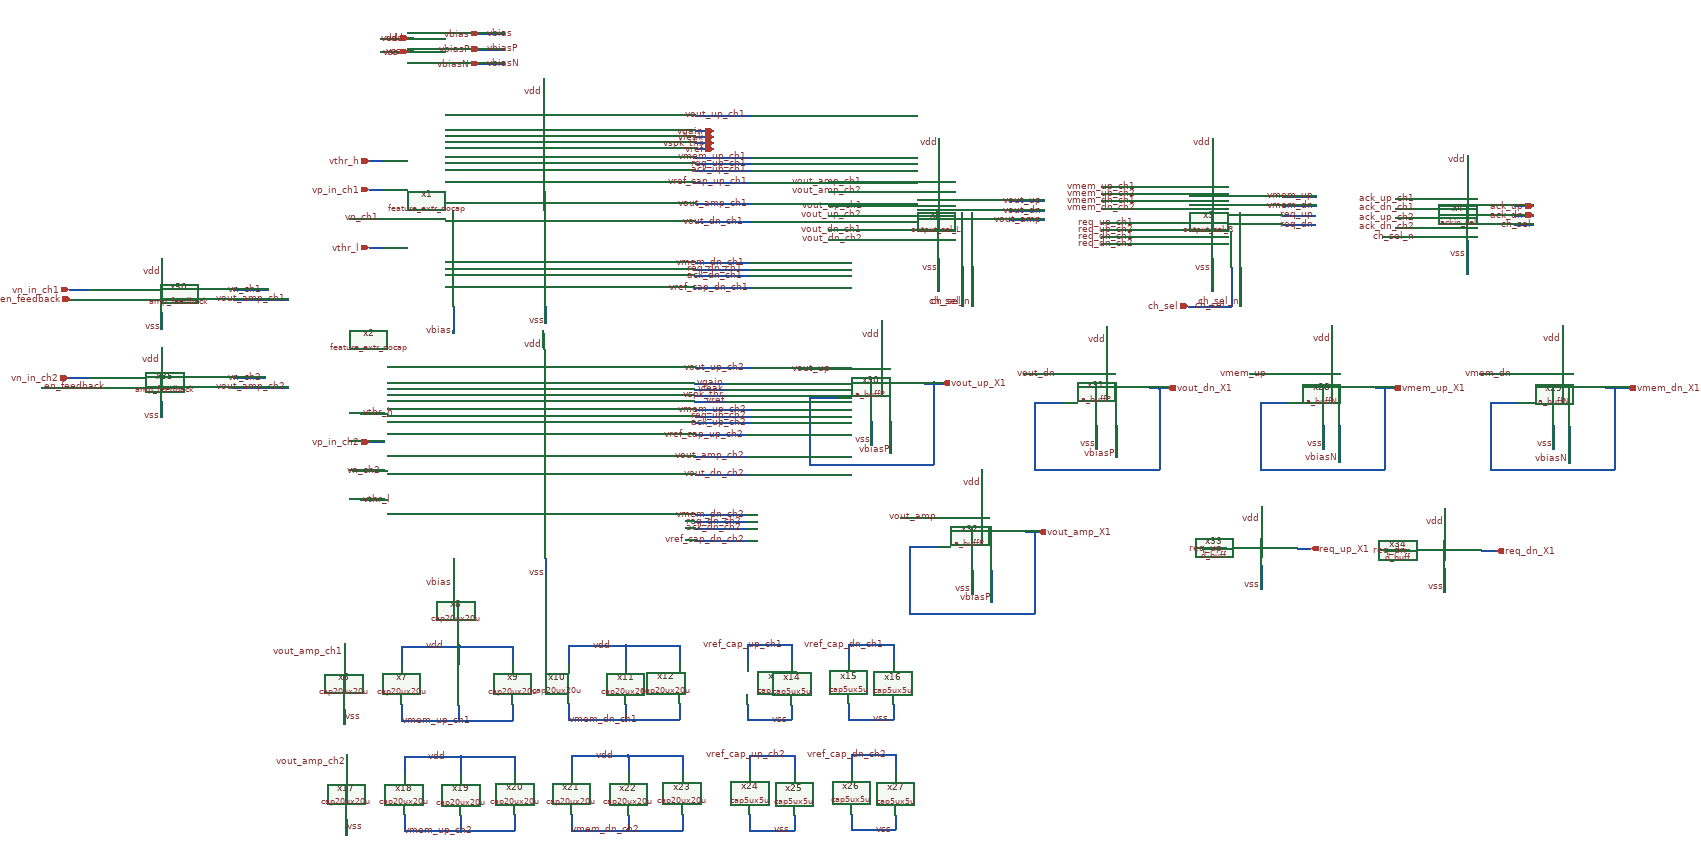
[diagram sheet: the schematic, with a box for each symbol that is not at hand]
v {xschem version=3.4.8RC file_version=1.3}
G {}
K {}
V {}
S {}
F {}
E {}
N 186.25 -1198.75 253.75 -1198.75 {lab=vdd}
N 186.25 -1171.25 253.75 -1171.25 {lab=vss}
N 388.75 -1208.75 443.75 -1208.75 {lab=vbias}
N 525 -1115 525 -1080 {lab=vdd}
N 530 -638.75 530 -603.75 {lab=vss}
N 525 -583.75 525 -555 {lab=vdd}
N 337.5 -640 337.5 -582.5 {lab=vbias}
N 530 -113.75 530 -78.75 {lab=vss}
N 337.5 -115 337.5 -57.5 {lab=vbias}
N 162.5 -943.75 193.75 -943.75 {lab=vthr_h}
N 162.5 -762.5 193.75 -762.5 {lab=vthr_l}
N 162.5 -883.75 193.75 -883.75 {lab=vp_in_ch1}
N 143.75 -417.5 193.75 -417.5 {lab=vthr_h}
N 143.75 -236.25 193.75 -236.25 {lab=vthr_l}
N 842.5 -1006.25 880 -1006.25 {lab=vgain}
N 842.5 -993.75 880 -993.75 {lab=vleak}
N 842.5 -981.25 880 -981.25 {lab=vspk_thr}
N 842.5 -968.75 880 -968.75 {lab=vref}
N 842.5 -937.5 962.5 -937.5 {lab=req_up_ch1}
N 842.5 -1038.75 961.25 -1038.75 {lab=vout_up_ch1}
N 842.5 -816.25 961.25 -816.25 {lab=vout_dn_ch1}
N 842.5 -411.25 960 -411.25 {lab=req_up_ch2}
N 842.5 -512.5 960 -512.5 {lab=vout_up_ch2}
N 843.75 -397.5 960 -397.5 {lab=ack_up_ch2}
N 843.75 -177.5 952.5 -177.5 {lab=ack_dn_ch2}
N 842.5 -923.75 962.5 -923.75 {lab=ack_up_ch1}
N 841.25 -703.75 957.5 -703.75 {lab=ack_dn_ch1}
N 841.25 -717.5 956.25 -717.5 {lab=req_dn_ch1}
N 842.5 -290 953.75 -290 {lab=vout_dn_ch2}
N 842.5 -372.5 946.25 -372.5 {lab=vref_cap_up_ch2}
N 842.5 -898.75 957.5 -898.75 {lab=vref_cap_up_ch1}
N 841.25 -191.25 951.25 -191.25 {lab=req_dn_ch2}
N 838.75 -951.25 962.5 -951.25 {lab=vmem_up_ch1}
N 842.5 -853.75 958.75 -853.75 {lab=vout_amp_ch1}
N 842.5 -731.25 956.25 -731.25 {lab=vmem_dn_ch1}
N 841.25 -678.75 958.75 -678.75 {lab=vref_cap_dn_ch1}
N 110 63.75 110 110 {lab=vout_amp_ch1}
N 110 200 110 232.5 {lab=vss}
N 230 190 230 223.75 {lab=vmem_up_ch1}
N 461.25 190 461.25 223.75 {lab=vmem_up_ch1}
N 348.75 192.5 348.75 223.75 {lab=vmem_up_ch1}
N 230 68.75 230 106.25 {lab=vdd}
N 461.25 68.75 461.25 105 {lab=vdd}
N 348.75 68.75 348.75 106.25 {lab=vdd}
N 842.5 -425 958.75 -425 {lab=vmem_up_ch2}
N 842.5 -327.5 951.25 -327.5 {lab=vout_amp_ch2}
N 842.5 -205 950 -205 {lab=vmem_dn_ch2}
N 841.25 -152.5 951.25 -152.5 {lab=vref_cap_dn_ch2}
N 841.25 -480 907.5 -480 {lab=vgain}
N 841.25 -467.5 907.5 -467.5 {lab=vleak}
N 841.25 -455 907.5 -455 {lab=vspk_thr}
N 841.25 -442.5 907.5 -442.5 {lab=vref}
N 162.5 -357.5 193.75 -357.5 {lab=vp_in_ch2}
N 1960 -720 1960 -640 {lab=ch_sel}
N 1870 -640 1960 -640 {lab=ch_sel}
N 1920 -740 1920 -670 {lab=vss}
N 1920 -990 1920 -930 {lab=vdd}
N 1120 -900 1200 -900 {lab=vout_amp_ch1}
N 1120 -880 1200 -880 {lab=vout_amp_ch2}
N 1120 -850 1200 -850 {lab=vout_up_ch1}
N 1120 -830 1200 -830 {lab=vout_up_ch2}
N 1120 -800 1200 -800 {lab=vout_dn_ch1}
N 1120 -780 1200 -780 {lab=vout_dn_ch2}
N 1690 -890 1770 -890 {lab=vmem_up_ch1}
N 1690 -875 1770 -875 {lab=vmem_up_ch2}
N 1690 -860 1770 -860 {lab=vmem_dn_ch1}
N 1690 -845 1770 -845 {lab=vmem_dn_ch2}
N 1690 -815 1770 -815 {lab=req_up_ch1}
N 1690 -800 1770 -800 {lab=req_up_ch2}
N 1690 -785 1770 -785 {lab=req_dn_ch1}
N 1690 -770 1770 -770 {lab=req_dn_ch2}
N 2067.5 -850 2137.5 -850 {lab=vmem_dn}
N 2067.5 -830 2135 -830 {lab=req_up}
N 2452.5 -955 2452.5 -895 {lab=vdd}
N 2452.5 -776.25 2452.5 -706.25 {lab=vss}
N 2550 -810 2591.25 -810 {lab=ch_sel}
N 2550 -830 2591.25 -830 {lab=ack_dn}
N 2550 -850 2591.25 -850 {lab=ack_up}
N 2302.5 -865 2352.5 -865 {lab=ack_up_ch1}
N 2302.5 -845 2352.5 -845 {lab=ack_dn_ch1}
N 2302.5 -825 2352.5 -825 {lab=ack_up_ch2}
N 2302.5 -805 2352.5 -805 {lab=ack_dn_ch2}
N 1980 -720 1980 -640 {lab=ch_sel_n}
N 2275 -785 2355 -785 {lab=ch_sel_n}
N 1420 -723.75 1420 -640 {lab=ch_sel_n}
N 1400 -723.75 1400 -640 {lab=ch_sel}
N 1350 -990 1350 -930 {lab=vdd}
N 1350 -740 1350 -670 {lab=vss}
N 230 68.75 348.75 68.75 {lab=vdd}
N 348.75 68.75 461.25 68.75 {lab=vdd}
N 230 223.75 348.75 223.75 {lab=vmem_up_ch1}
N 348.75 223.75 461.25 223.75 {lab=vmem_up_ch1}
N 578.75 188.75 578.75 222.5 {lab=vmem_dn_ch1}
N 810 188.75 810 222.5 {lab=vmem_dn_ch1}
N 697.5 191.25 697.5 222.5 {lab=vmem_dn_ch1}
N 578.75 67.5 578.75 105 {lab=vdd}
N 810 67.5 810 103.75 {lab=vdd}
N 697.5 67.5 697.5 105 {lab=vdd}
N 578.75 67.5 697.5 67.5 {lab=vdd}
N 697.5 67.5 810 67.5 {lab=vdd}
N 578.75 222.5 697.5 222.5 {lab=vmem_dn_ch1}
N 697.5 222.5 810 222.5 {lab=vmem_dn_ch1}
N 951.25 66.25 951.25 101.25 {lab=vref_cap_up_ch1}
N 1043.75 66.25 1043.75 103.75 {lab=vref_cap_up_ch1}
N 951.25 66.25 1043.75 66.25 {lab=vref_cap_up_ch1}
N 951.25 190 951.25 222.5 {lab=vss}
N 951.25 222.5 1043.75 222.5 {lab=vss}
N 1043.75 192.5 1043.75 222.5 {lab=vss}
N 1162.5 65 1162.5 100 {lab=vref_cap_dn_ch1}
N 1255 65 1255 102.5 {lab=vref_cap_dn_ch1}
N 1162.5 65 1255 65 {lab=vref_cap_dn_ch1}
N 1162.5 188.75 1162.5 221.25 {lab=vss}
N 1162.5 221.25 1255 221.25 {lab=vss}
N 1255 191.25 1255 221.25 {lab=vss}
N 115 293.75 115 340 {lab=vout_amp_ch2}
N 115 430 115 462.5 {lab=vss}
N 235 420 235 453.75 {lab=vmem_up_ch2}
N 466.25 420 466.25 453.75 {lab=vmem_up_ch2}
N 353.75 422.5 353.75 453.75 {lab=vmem_up_ch2}
N 235 298.75 235 336.25 {lab=vdd}
N 466.25 298.75 466.25 335 {lab=vdd}
N 353.75 298.75 353.75 336.25 {lab=vdd}
N 235 298.75 353.75 298.75 {lab=vdd}
N 353.75 298.75 466.25 298.75 {lab=vdd}
N 235 453.75 353.75 453.75 {lab=vmem_up_ch2}
N 353.75 453.75 466.25 453.75 {lab=vmem_up_ch2}
N 583.75 418.75 583.75 452.5 {lab=vmem_dn_ch2}
N 815 418.75 815 452.5 {lab=vmem_dn_ch2}
N 702.5 421.25 702.5 452.5 {lab=vmem_dn_ch2}
N 583.75 297.5 583.75 335 {lab=vdd}
N 815 297.5 815 333.75 {lab=vdd}
N 702.5 297.5 702.5 335 {lab=vdd}
N 583.75 297.5 702.5 297.5 {lab=vdd}
N 702.5 297.5 815 297.5 {lab=vdd}
N 583.75 452.5 702.5 452.5 {lab=vmem_dn_ch2}
N 702.5 452.5 815 452.5 {lab=vmem_dn_ch2}
N 956.25 296.25 956.25 331.25 {lab=vref_cap_up_ch2}
N 1048.75 296.25 1048.75 333.75 {lab=vref_cap_up_ch2}
N 956.25 296.25 1048.75 296.25 {lab=vref_cap_up_ch2}
N 956.25 420 956.25 452.5 {lab=vss}
N 956.25 452.5 1048.75 452.5 {lab=vss}
N 1048.75 422.5 1048.75 452.5 {lab=vss}
N 1167.5 295 1167.5 330 {lab=vref_cap_dn_ch2}
N 1260 295 1260 332.5 {lab=vref_cap_dn_ch2}
N 1167.5 295 1260 295 {lab=vref_cap_dn_ch2}
N 1167.5 418.75 1167.5 451.25 {lab=vss}
N 1167.5 451.25 1260 451.25 {lab=vss}
N 1260 421.25 1260 451.25 {lab=vss}
N 1290 -140 1350 -140 {lab=vout_amp_X1}
N 1290 -140 1290 0 {lab=vout_amp_X1}
N 1290 0 1550 0 {lab=vout_amp_X1}
N 1550 -170 1550 0 {lab=vout_amp_X1}
N 1530 -170 1550 -170 {lab=vout_amp_X1}
N 1080 -450 1140 -450 {lab=vout_up_X1}
N 1080 -450 1080 -310 {lab=vout_up_X1}
N 1080 -310 1340 -310 {lab=vout_up_X1}
N 1340 -480 1340 -310 {lab=vout_up_X1}
N 1320 -480 1340 -480 {lab=vout_up_X1}
N 1550 -440 1610 -440 {lab=vout_dn_X1}
N 1550 -440 1550 -300 {lab=vout_dn_X1}
N 1550 -300 1810 -300 {lab=vout_dn_X1}
N 1810 -470 1810 -300 {lab=vout_dn_X1}
N 1790 -470 1810 -470 {lab=vout_dn_X1}
N 2020 -440 2080 -440 {lab=vmem_up_X1}
N 2020 -440 2020 -300 {lab=vmem_up_X1}
N 2020 -300 2280 -300 {lab=vmem_up_X1}
N 2280 -470 2280 -300 {lab=vmem_up_X1}
N 2260 -470 2280 -470 {lab=vmem_up_X1}
N 2500 -440 2560 -440 {lab=vmem_dn_X1}
N 2500 -440 2500 -300 {lab=vmem_dn_X1}
N 2500 -300 2760 -300 {lab=vmem_dn_X1}
N 2760 -470 2760 -300 {lab=vmem_dn_X1}
N 2760 -470 2790 -470 {lab=vmem_dn_X1}
N 2740 -470 2760 -470 {lab=vmem_dn_X1}
N 1270 -200 1350 -200 {lab=vout_amp}
N 1057.5 -510 1140 -510 {lab=vout_up}
N 1527.5 -500 1610 -500 {lab=vout_dn}
N 1997.5 -500 2080 -500 {lab=vmem_up}
N 2477.5 -500 2560 -500 {lab=vmem_dn}
N 1420 -90 1420 -40 {lab=vss}
N 1440 -300 1440 -250 {lab=vdd}
N 1460 -90 1460 -22.5 {lab=vbiasP}
N 1700 -598.75 1700 -548.75 {lab=vdd}
N 1680 -391.25 1680 -341.25 {lab=vss}
N 1720 -391.25 1720 -323.75 {lab=vbiasP}
N 1210 -400 1210 -350 {lab=vss}
N 1250 -400 1250 -332.5 {lab=vbiasP}
N 1230 -610 1230 -560 {lab=vdd}
N 2170 -600 2170 -550 {lab=vdd}
N 2650 -600 2650 -550 {lab=vdd}
N 2152.5 -391.25 2152.5 -341.25 {lab=vss}
N 2632.5 -391.25 2632.5 -341.25 {lab=vss}
N 2185 -391.25 2185 -313.75 {lab=vbiasN}
N 2665 -390 2665 -312.5 {lab=vbiasN}
N 1340 -480 1360 -480 {lab=vout_up_X1}
N 1810 -470 1830 -470 {lab=vout_dn_X1}
N 1550 -170 1560 -170 {lab=vout_amp_X1}
N 1497.5 -860 1570 -860 {lab=vout_up}
N 1497.5 -840 1570 -840 {lab=vout_dn}
N 1497.5 -820 1570 -820 {lab=vout_amp}
N 2280 -470 2300 -470 {lab=vmem_up_X1}
N 1900 -135 1950 -135 {lab=req_up}
N 2022.5 -222.5 2022.5 -172.5 {lab=vdd}
N 2022.5 -98.75 2022.5 -48.75 {lab=vss}
N 2067.5 -870 2137.5 -870 {lab=vmem_up}
N 2282.5 -130 2332.5 -130 {lab=req_dn}
N 2405 -217.5 2405 -167.5 {lab=vdd}
N 2405 -93.75 2405 -43.75 {lab=vss}
N 2097.5 -135 2125 -135 {lab=req_up_X1}
N 2482.5 -130 2512.5 -130 {lab=req_dn_X1}
N 2067.5 -810 2135 -810 {lab=req_dn}
N 388.75 -1176.25 443.75 -1176.25 {lab=vbiasP}
N 388.75 -1146.25 443.75 -1146.25 {lab=vbiasN}
N 127.5 -297.5 195 -297.5 {lab=vn_ch2}
N 121.25 -823.75 195 -823.75 {lab=vn_ch1}
N -121.25 -675 -47.5 -675 {lab=vn_ch1}
N -121.25 -655 -5 -655 {lab=vout_amp_ch1}
N -462.5 -675 -420 -675 {lab=vn_in_ch1}
N -462.5 -655 -420 -655 {lab=en_feedback}
N -270 -740 -270 -705 {lab=vdd}
N -270 -626.25 -270 -591.25 {lab=vss}
N -271.25 -555 -271.25 -520 {lab=vdd}
N -271.25 -442.5 -271.25 -407.5 {lab=vss}
N -121.25 -491.25 -53.75 -491.25 {lab=vn_ch2}
N -122.5 -471.25 -6.25 -471.25 {lab=vout_amp_ch2}
N -465 -491.25 -420 -491.25 {lab=vn_in_ch2}
N -520 -471.25 -421.25 -471.25 {lab=#net2}
C {feature_extr_nocap.sym} 523.75 -858.75 0 0 {name=x1}
C {feature_extr_nocap.sym} 523.75 -332.5 0 0 {name=x2}
C {iopin.sym} 243.75 -1198.75 0 0 {name=pin_vdd lab=vdd}
C {iopin.sym} 243.75 -1171.25 0 0 {name=pin_vss lab=vss}
C {lab_wire.sym} 196.25 -1198.75 2 0 {name=p16 sig_type=std_logic lab=vdd
}
C {lab_wire.sym} 196.25 -1171.25 2 0 {name=p17 sig_type=std_logic lab=vss
}
C {ipin.sym} 391.25 -1208.75 0 0 {name=pin_vbias lab=vbias}
C {lab_wire.sym} 406.25 -1208.75 2 0 {name=p18 sig_type=std_logic lab=vbias
}
C {lab_wire.sym} 525 -1087.5 1 0 {name=p1 sig_type=std_logic lab=vdd
}
C {lab_wire.sym} 530 -608.75 1 0 {name=p2 sig_type=std_logic lab=vss
}
C {lab_wire.sym} 525 -558.75 1 0 {name=p3 sig_type=std_logic lab=vdd
}
C {lab_wire.sym} 337.5 -588.75 1 0 {name=p4 sig_type=std_logic lab=vbias
}
C {lab_wire.sym} 530 -83.75 1 0 {name=p5 sig_type=std_logic lab=vss
}
C {lab_wire.sym} 337.5 -63.75 1 0 {name=p6 sig_type=std_logic lab=vbias
}
C {ipin.sym} 162.5 -943.75 0 0 {name=pin_vthr_h lab=vthr_h}
C {ipin.sym} 162.5 -762.5 0 0 {name=pin_vthr_l lab=vthr_l}
C {lab_wire.sym} 147.5 -417.5 2 0 {name=p7 sig_type=std_logic lab=vthr_h
}
C {lab_wire.sym} 147.5 -236.25 2 0 {name=p8 sig_type=std_logic lab=vthr_l
}
C {ipin.sym} 880 -1006.25 2 0 {name=pin_vgain lab=vgain}
C {ipin.sym} 880 -993.75 2 0 {name=pin_vleak lab=vleak}
C {ipin.sym} 880 -981.25 2 0 {name=pin_vspkthr lab=vspk_thr}
C {ipin.sym} 880 -968.75 2 0 {name=pin_vref lab=vref}
C {lab_wire.sym} 955 -853.75 0 0 {name=p42 sig_type=std_logic lab=vout_amp_ch1
}
C {lab_wire.sym} 950 -1038.75 0 0 {name=p57 sig_type=std_logic lab=vout_up_ch1
}
C {lab_wire.sym} 945 -816.25 0 0 {name=p58 sig_type=std_logic lab=vout_dn_ch1
}
C {lab_wire.sym} 951.25 -951.25 0 0 {name=p59 sig_type=std_logic lab=vmem_up_ch1
}
C {lab_wire.sym} 947.5 -731.25 0 0 {name=p62 sig_type=std_logic lab=vmem_dn_ch1
}
C {lab_wire.sym} 947.5 -512.5 0 0 {name=p63 sig_type=std_logic lab=vout_up_ch2
}
C {lab_wire.sym} 952.5 -425 0 0 {name=p64 sig_type=std_logic lab=vmem_up_ch2
}
C {lab_wire.sym} 948.75 -327.5 0 0 {name=p34 sig_type=std_logic lab=vout_amp_ch2
}
C {lab_wire.sym} 948.75 -290 0 0 {name=p66 sig_type=std_logic lab=vout_dn_ch2
}
C {lab_wire.sym} 947.5 -205 0 0 {name=p67 sig_type=std_logic lab=vmem_dn_ch2
}
C {ipin.sym} 162.5 -883.75 0 0 {name=pin_vpin_ch1 lab=vp_in_ch1}
C {lab_wire.sym} 955 -898.75 0 0 {name=p13 sig_type=std_logic lab=vref_cap_up_ch1
}
C {lab_wire.sym} 956.25 -678.75 0 0 {name=p14 sig_type=std_logic lab=vref_cap_dn_ch1
}
C {lab_wire.sym} 110 216.25 2 0 {name=p76 sig_type=std_logic lab=vss}
C {lab_wire.sym} 110 80 0 0 {name=p77 sig_type=std_logic lab=vout_amp_ch1}
C {lab_wire.sym} 376.25 223.75 0 0 {name=p78 sig_type=std_logic lab=vmem_up_ch1}
C {lab_wire.sym} 278.75 68.75 2 0 {name=p79 sig_type=std_logic lab=vdd}
C {lab_wire.sym} 1000 222.5 2 0 {name=p82 sig_type=std_logic lab=vss}
C {lab_wire.sym} 1027.5 66.25 0 0 {name=p83 sig_type=std_logic lab=vref_cap_up_ch1}
C {lab_wire.sym} 948.75 -152.5 0 0 {name=p15 sig_type=std_logic lab=vref_cap_dn_ch2
}
C {lab_wire.sym} 945 -372.5 0 0 {name=p19 sig_type=std_logic lab=vref_cap_up_ch2
}
C {lab_wire.sym} 904.375 -480 0 0 {name=p9 sig_type=std_logic lab=vgain}
C {lab_wire.sym} 904.375 -467.5 0 0 {name=p10 sig_type=std_logic lab=vleak}
C {lab_wire.sym} 905 -455 0 0 {name=p11 sig_type=std_logic lab=vspk_thr}
C {lab_wire.sym} 905.625 -442.5 0 0 {name=p12 sig_type=std_logic lab=vref}
C {ipin.sym} 162.5 -357.5 0 0 {name=pin_vpin_ch2 lab=vp_in_ch2}
C {output_sel_R.sym} 1920 -830 0 0 {name=x3}
C {lab_wire.sym} 1950 -640 0 0 {name=p26 sig_type=std_logic lab=ch_sel}
C {lab_wire.sym} 1920 -720 3 0 {name=p27 sig_type=std_logic lab=vss}
C {lab_wire.sym} 1920 -980 3 0 {name=p28 sig_type=std_logic lab=vdd}
C {lab_wire.sym} 1192.5 -900 0 0 {name=p29 sig_type=std_logic lab=vout_amp_ch1
}
C {lab_wire.sym} 1192.5 -880 0 0 {name=p35 sig_type=std_logic lab=vout_amp_ch2
}
C {lab_wire.sym} 1193.75 -850 0 0 {name=p36 sig_type=std_logic lab=vout_up_ch1
}
C {lab_wire.sym} 1192.5 -800 0 0 {name=p37 sig_type=std_logic lab=vout_dn_ch1
}
C {lab_wire.sym} 1192.5 -830 0 0 {name=p38 sig_type=std_logic lab=vout_up_ch2
}
C {lab_wire.sym} 1195 -780 0 0 {name=p39 sig_type=std_logic lab=vout_dn_ch2
}
C {lab_wire.sym} 1762.5 -890 0 0 {name=p40 sig_type=std_logic lab=vmem_up_ch1
}
C {lab_wire.sym} 1762.5 -860 0 0 {name=p41 sig_type=std_logic lab=vmem_dn_ch1
}
C {lab_wire.sym} 1763.75 -875 0 0 {name=p43 sig_type=std_logic lab=vmem_up_ch2
}
C {lab_wire.sym} 1762.5 -845 0 0 {name=p44 sig_type=std_logic lab=vmem_dn_ch2
}
C {lab_wire.sym} 1760 -815 0 0 {name=p45 sig_type=std_logic lab=req_up_ch1
}
C {lab_wire.sym} 1760 -800 0 0 {name=p46 sig_type=std_logic lab=req_up_ch2
}
C {lab_wire.sym} 1760 -785 0 0 {name=p47 sig_type=std_logic lab=req_dn_ch1
}
C {lab_wire.sym} 1760 -770 0 0 {name=p48 sig_type=std_logic lab=req_dn_ch2
}
C {opin.sym} 1557.5 -170 0 0 {name=pin_voutamp_X1 lab=vout_amp_X1}
C {opin.sym} 1357.5 -480 0 0 {name=pin_voutup_X1 lab=vout_up_X1}
C {opin.sym} 1827.5 -470 0 0 {name=pin_voutdn_X1 lab=vout_dn_X1}
C {opin.sym} 2296.25 -470 0 0 {name=pin_vmemup_X1 lab=vmem_up_X1}
C {opin.sym} 2787.5 -470 0 0 {name=pin_vmemdn_X1 lab=vmem_dn_X1}
C {opin.sym} 2125 -135 0 0 {name=pin_requp_X1 lab=req_up_X1}
C {opin.sym} 2512.5 -130 0 0 {name=pin_reqdn_X1 lab=req_dn_X1}
C {ackin_sel.sym} 2452.5 -835 0 1 {name=x4}
C {lab_wire.sym} 2452.5 -945 3 0 {name=p49 sig_type=std_logic lab=vdd}
C {lab_wire.sym} 2452.5 -748.75 3 0 {name=p50 sig_type=std_logic lab=vss}
C {lab_wire.sym} 2590 -810 0 0 {name=p51 sig_type=std_logic lab=ch_sel}
C {ipin.sym} 2590 -850 2 0 {name=pin_ackup lab=ack_up}
C {ipin.sym} 2590 -830 2 0 {name=pin_ackdn lab=ack_dn}
C {lab_wire.sym} 2345 -865 0 0 {name=p52 sig_type=std_logic lab=ack_up_ch1
}
C {lab_wire.sym} 2345 -845 0 0 {name=p53 sig_type=std_logic lab=ack_dn_ch1
}
C {lab_wire.sym} 2345 -825 0 0 {name=p54 sig_type=std_logic lab=ack_up_ch2
}
C {lab_wire.sym} 2345 -805 0 0 {name=p55 sig_type=std_logic lab=ack_dn_ch2
}
C {lab_wire.sym} 951.25 -937.5 0 0 {name=p56 sig_type=std_logic lab=req_up_ch1
}
C {lab_wire.sym} 952.5 -923.75 0 0 {name=p60 sig_type=std_logic lab=ack_up_ch1
}
C {lab_wire.sym} 943.75 -717.5 0 0 {name=p61 sig_type=std_logic lab=req_dn_ch1
}
C {lab_wire.sym} 943.75 -703.75 0 0 {name=p65 sig_type=std_logic lab=ack_dn_ch1
}
C {lab_wire.sym} 952.5 -411.25 0 0 {name=p68 sig_type=std_logic lab=req_up_ch2
}
C {lab_wire.sym} 952.5 -397.5 0 0 {name=p69 sig_type=std_logic lab=ack_up_ch2
}
C {lab_wire.sym} 941.25 -191.25 0 0 {name=p70 sig_type=std_logic lab=req_dn_ch2
}
C {lab_wire.sym} 941.25 -177.5 0 0 {name=p71 sig_type=std_logic lab=ack_dn_ch2
}
C {ipin.sym} 1870 -640 0 0 {name=pin_chsel lab=ch_sel}
C {output_sel_L.sym} 1350 -840 0 0 {name=x5}
C {lab_wire.sym} 1980 -650 1 0 {name=p72 sig_type=std_logic lab=ch_sel_n}
C {lab_wire.sym} 2345 -785 0 0 {name=p73 sig_type=std_logic lab=ch_sel_n}
C {lab_wire.sym} 1420 -650 1 0 {name=p74 sig_type=std_logic lab=ch_sel_n}
C {lab_wire.sym} 1400 -650 1 0 {name=p75 sig_type=std_logic lab=ch_sel}
C {lab_wire.sym} 1350 -980 3 0 {name=p86 sig_type=std_logic lab=vdd}
C {lab_wire.sym} 1350 -720 3 0 {name=p87 sig_type=std_logic lab=vss}
C {cap20ux20u.sym} 110 160 0 0 {name=x6}
C {cap20ux20u.sym} 230 152.5 0 0 {name=x7}
C {cap20ux20u.sym} 348.75 152.5 0 0 {name=x8}
C {cap20ux20u.sym} 461.25 152.5 0 0 {name=x9}
C {lab_wire.sym} 725 222.5 0 0 {name=p80 sig_type=std_logic lab=vmem_dn_ch1}
C {lab_wire.sym} 627.5 67.5 2 0 {name=p81 sig_type=std_logic lab=vdd}
C {cap20ux20u.sym} 578.75 151.25 0 0 {name=x10}
C {cap20ux20u.sym} 697.5 151.25 0 0 {name=x11}
C {cap20ux20u.sym} 810 151.25 0 0 {name=x12}
C {cap5ux5u.sym} 951.25 141.25 0 0 {name=x13}
C {cap5ux5u.sym} 1043.75 143.75 0 0 {name=x14}
C {lab_wire.sym} 1211.25 221.25 2 0 {name=p84 sig_type=std_logic lab=vss}
C {lab_wire.sym} 1238.75 65 0 0 {name=p85 sig_type=std_logic lab=vref_cap_dn_ch1}
C {cap5ux5u.sym} 1162.5 140 0 0 {name=x15}
C {cap5ux5u.sym} 1255 142.5 0 0 {name=x16}
C {lab_wire.sym} 115 446.25 2 0 {name=p20 sig_type=std_logic lab=vss}
C {lab_wire.sym} 115 310 0 0 {name=p21 sig_type=std_logic lab=vout_amp_ch2}
C {lab_wire.sym} 381.25 453.75 0 0 {name=p22 sig_type=std_logic lab=vmem_up_ch2}
C {lab_wire.sym} 283.75 298.75 2 0 {name=p23 sig_type=std_logic lab=vdd}
C {lab_wire.sym} 1005 452.5 2 0 {name=p24 sig_type=std_logic lab=vss}
C {lab_wire.sym} 1032.5 296.25 0 0 {name=p25 sig_type=std_logic lab=vref_cap_up_ch2}
C {cap20ux20u.sym} 115 390 0 0 {name=x17}
C {cap20ux20u.sym} 235 382.5 0 0 {name=x18}
C {cap20ux20u.sym} 353.75 382.5 0 0 {name=x19}
C {cap20ux20u.sym} 466.25 382.5 0 0 {name=x20}
C {lab_wire.sym} 730 452.5 0 0 {name=p30 sig_type=std_logic lab=vmem_dn_ch2}
C {lab_wire.sym} 632.5 297.5 2 0 {name=p31 sig_type=std_logic lab=vdd}
C {cap20ux20u.sym} 583.75 381.25 0 0 {name=x21}
C {cap20ux20u.sym} 702.5 381.25 0 0 {name=x22}
C {cap20ux20u.sym} 815 381.25 0 0 {name=x23}
C {cap5ux5u.sym} 956.25 371.25 0 0 {name=x24}
C {cap5ux5u.sym} 1048.75 373.75 0 0 {name=x25}
C {lab_wire.sym} 1216.25 451.25 2 0 {name=p32 sig_type=std_logic lab=vss}
C {lab_wire.sym} 1243.75 295 0 0 {name=p33 sig_type=std_logic lab=vref_cap_dn_ch2}
C {cap5ux5u.sym} 1167.5 370 0 0 {name=x26}
C {cap5ux5u.sym} 1260 372.5 0 0 {name=x27}
C {a_buffN.sym} 2170 -470 0 0 {name=x28}
C {a_buffN.sym} 2650 -470 0 0 {name=x29}
C {a_buffP.sym} 1210 -480 0 0 {name=x30}
C {a_buffP.sym} 1680 -470 0 0 {name=x31}
C {a_buffP.sym} 1420 -170 0 0 {name=x32}
C {devices/lab_wire.sym} 1347.5 -200 0 0 {name=p88 sig_type=std_logic lab=vout_amp}
C {devices/lab_wire.sym} 1127.5 -510 0 0 {name=p89 sig_type=std_logic lab=vout_up}
C {devices/lab_wire.sym} 1597.5 -500 0 0 {name=p90 sig_type=std_logic lab=vout_dn}
C {devices/lab_wire.sym} 2037.5 -500 0 0 {name=p91 sig_type=std_logic lab=vmem_up}
C {devices/lab_wire.sym} 2547.5 -500 0 0 {name=p92 sig_type=std_logic lab=vmem_dn}
C {lab_wire.sym} 1420 -51.25 1 0 {name=p94 sig_type=std_logic lab=vss}
C {lab_wire.sym} 1440 -271.25 1 0 {name=p95 sig_type=std_logic lab=vdd}
C {lab_wire.sym} 1460 -31.25 1 0 {name=p96 sig_type=std_logic lab=vbiasP}
C {lab_wire.sym} 1700 -570 1 0 {name=p97 sig_type=std_logic lab=vdd}
C {lab_wire.sym} 1680 -352.5 1 0 {name=p98 sig_type=std_logic lab=vss}
C {lab_wire.sym} 1720 -332.5 1 0 {name=p99 sig_type=std_logic lab=vbiasP}
C {lab_wire.sym} 1210 -361.25 1 0 {name=p100 sig_type=std_logic lab=vss}
C {lab_wire.sym} 1250 -341.25 1 0 {name=p101 sig_type=std_logic lab=vbiasP}
C {lab_wire.sym} 1230 -581.25 1 0 {name=p102 sig_type=std_logic lab=vdd}
C {lab_wire.sym} 2170 -571.25 1 0 {name=p107 sig_type=std_logic lab=vdd}
C {lab_wire.sym} 2650 -571.25 1 0 {name=p108 sig_type=std_logic lab=vdd}
C {lab_wire.sym} 2152.5 -352.5 1 0 {name=p109 sig_type=std_logic lab=vss}
C {lab_wire.sym} 2632.5 -352.5 1 0 {name=p110 sig_type=std_logic lab=vss}
C {lab_wire.sym} 2185 -323.75 1 0 {name=p111 sig_type=std_logic lab=vbiasN}
C {lab_wire.sym} 2665 -322.5 1 0 {name=p112 sig_type=std_logic lab=vbiasN}
C {devices/lab_wire.sym} 1567.5 -860 0 0 {name=p93 sig_type=std_logic lab=vout_up}
C {devices/lab_wire.sym} 1567.5 -840 0 0 {name=p103 sig_type=std_logic lab=vout_dn}
C {devices/lab_wire.sym} 1567.5 -820 0 0 {name=p104 sig_type=std_logic lab=vout_amp}
C {d_buff.sym} 2030 -135 0 0 {name=x33}
C {lab_wire.sym} 2022.5 -196.25 1 0 {name=p105 sig_type=std_logic lab=vdd}
C {lab_wire.sym} 2022.5 -60 1 0 {name=p106 sig_type=std_logic lab=vss}
C {devices/lab_wire.sym} 2135 -870 0 0 {name=p113 sig_type=std_logic lab=vmem_up}
C {devices/lab_wire.sym} 2135 -850 0 0 {name=p114 sig_type=std_logic lab=vmem_dn}
C {d_buff.sym} 2412.5 -130 0 0 {name=x34}
C {lab_wire.sym} 2405 -191.25 1 0 {name=p115 sig_type=std_logic lab=vdd}
C {lab_wire.sym} 2405 -55 1 0 {name=p116 sig_type=std_logic lab=vss}
C {devices/lab_wire.sym} 2135 -830 0 0 {name=p117 sig_type=std_logic lab=req_up}
C {devices/lab_wire.sym} 2135 -810 0 0 {name=p118 sig_type=std_logic lab=req_dn}
C {devices/lab_wire.sym} 1945 -135 0 0 {name=p119 sig_type=std_logic lab=req_up}
C {devices/lab_wire.sym} 2327.5 -130 0 0 {name=p120 sig_type=std_logic lab=req_dn}
C {ipin.sym} 391.25 -1176.25 0 0 {name=pin_vbiasP lab=vbiasP}
C {lab_wire.sym} 406.25 -1176.25 2 0 {name=p121 sig_type=std_logic lab=vbiasP
}
C {ipin.sym} 391.25 -1146.25 0 0 {name=pin_vbias2 lab=vbiasN}
C {lab_wire.sym} 406.25 -1146.25 2 0 {name=p122 sig_type=std_logic lab=vbiasN
}
C {lab_wire.sym} 188.75 -297.5 0 0 {name=p129 sig_type=std_logic lab=vn_ch2
}
C {lab_wire.sym} 183.75 -823.75 0 0 {name=p146 sig_type=std_logic lab=vn_ch1
}
C {amp_feedback.sym} -270 -665 0 0 {name=x50}
C {lab_wire.sym} -58.75 -675 0 0 {name=p147 sig_type=std_logic lab=vn_ch1
}
C {lab_wire.sym} -8.75 -655 0 0 {name=p148 sig_type=std_logic lab=vout_amp_ch1
}
C {ipin.sym} -462.5 -675 0 0 {name=pin_vnin2 lab=vn_in_ch1}
C {ipin.sym} -461.25 -655 0 0 {name=pin_enfeedback1 lab=en_feedback}
C {lab_wire.sym} -270 -712.5 1 0 {name=p123 sig_type=std_logic lab=vdd
}
C {lab_wire.sym} -270 -596.25 1 0 {name=p124 sig_type=std_logic lab=vss
}
C {amp_feedback.sym} -271.25 -481.25 0 0 {name=x35}
C {lab_wire.sym} -271.25 -527.5 1 0 {name=p125 sig_type=std_logic lab=vdd
}
C {lab_wire.sym} -271.25 -412.5 1 0 {name=p130 sig_type=std_logic lab=vss
}
C {lab_wire.sym} -60 -491.25 0 0 {name=p131 sig_type=std_logic lab=vn_ch2
}
C {lab_wire.sym} -10 -471.25 0 0 {name=p138 sig_type=std_logic lab=vout_amp_ch2
}
C {ipin.sym} -465 -491.25 0 0 {name=pin_vnin3 lab=vn_in_ch2}
C {lab_wire.sym} -517.5 -471.25 2 0 {name=p139 sig_type=std_logic lab=en_feedback
}
